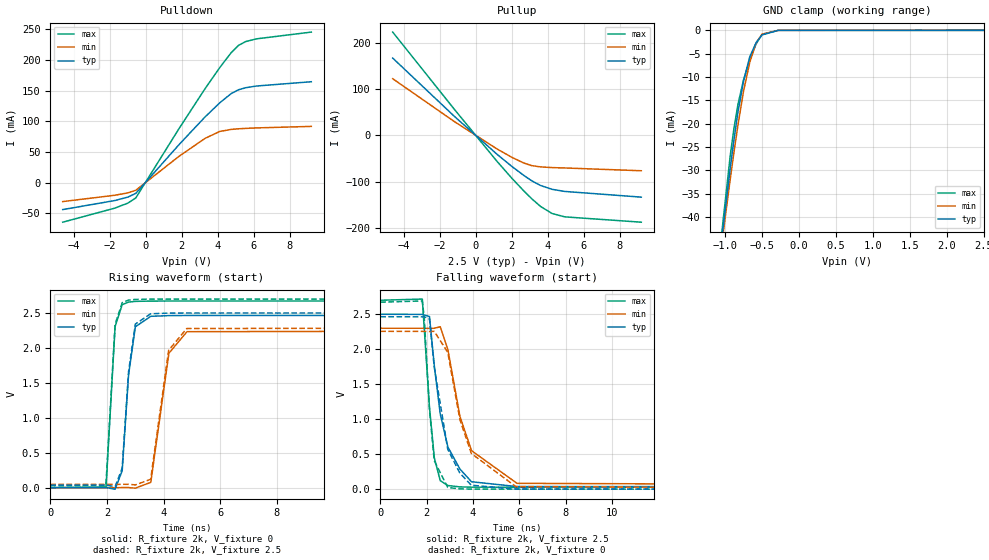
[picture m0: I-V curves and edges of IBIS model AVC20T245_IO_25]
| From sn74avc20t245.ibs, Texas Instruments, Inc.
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[Model]   AVC20T245_IO_25
Model_type  I/O
Vinl=0.7
Vinh=1.6
Enable   Active-Low
Vref =   0
Rref =   2000
Cref =   15p
Vmeas =   1.25
| variable   typ   min   max
C_comp   4.95pF   4.21pF   5.74pF
| C_pullup   4.12pF   3.17pF   5.55pF
| C_pulldown   4.24pF   3.76pF   4.72pF
| C_tri-state   4.95pF   4.21pF   5.74pF
[Temperature Range]   40   100   -40
| Ambient temperature   25   85   -40
[Voltage range]   2.5   2.3   2.7
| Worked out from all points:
|   slope of the pulldown table from 0 to 0.375 V, typ, clamps not added: 29.4 ohm
|   slope of the pullup table from 0 to 0.375 V, typ, clamps not added: 28.8 ohm
|   GND clamp passes 1 mA (typ) near -0.50 V on its own axis
|   rising waveform, R_fixture 2k, V_fixture 0: 20-80 % time 248ps typ, 381ps min, 173ps max; typ from 0 V to 2.46 V
|   falling waveform, R_fixture 2k, V_fixture 2.5: 20-80 % time 727ps typ, 1.03ns min, 342ps max; typ from 2.5 V to 0.036 V
|   rising waveform, R_fixture 2k, V_fixture 2.5: 20-80 % time 247ps typ, 377ps min, 173ps max; typ from 0.036 V to 2.5 V
|   falling waveform, R_fixture 2k, V_fixture 0: 20-80 % time 721ps typ, 1.03ns min, 334ps max; typ from 2.46 V to 0 V
[GND Clamp]
| AVC20T245_IO_25
|   Voltage   I(typ)   I(min)   I(max)
-4.6V     -597.8mA   -546.6mA   -662.5mA
-1.105V   -52.8mA    -53.15mA   -52.37mA
-1.08V    -49.35mA   -50.03mA   -48.48mA
-930mV    -29.5mA    -31.88mA   -26.82mA
-880mV    -23.45mA   -26.17mA   -21.02mA
-825mV    -17.44mA   -20.22mA   -15.81mA
-750mV    -10.86mA   -13.03mA   -10.61mA
-665mV    -5.629mA   -6.786mA   -6.326mA
-580mV    -2.642mA   -2.683mA   -2.914mA
-500mV    -988.4uA   -823.5uA   -890.7uA
-280mV    -5.263uA   -7.282uA   -1.131uA
2.5V      1.201nA    546.5nA    148.6pA
[Pulldown]
| AVC20T245_IO_25
|   Voltage   I(typ)   I(min)   I(max)
-4.6V     -43.76mA   -30.71mA   -64.27mA
-1.71V    -29.04mA   -20.44mA   -41.4mA
-985mV    -23.44mA   -16.53mA   -33.24mA
-545mV    -17.41mA   -12.35mA   -24.86mA
1.85V     61.76mA    42.85mA    87.78mA
3.295V    106.9mA    72.08mA    152.8mA
4.12V     130.1mA    83.49mA    187.5mA
4.755V    145.2mA    86.77mA    211.8mA
5.15V     151.2mA    87.75mA    223.4mA
5.55V     154.6mA    88.43mA    229.7mA
6.155V    157.4mA    89.2mA     234.2mA
9.2V      164.4mA    91.67mA    245.2mA
[Pullup]
| AVC20T245_IO_25
|   Voltage   I(typ)   I(min)   I(max)
-4.6V     167.2mA    122.6mA    223.3mA
-1.155V   40.55mA    29.45mA    55.44mA
1.195V    -40.71mA   -29.18mA   -56.05mA
2.025V    -67.14mA   -47.36mA   -92.77mA
2.69V     -86.59mA   -59.63mA   -120.2mA
3.115V    -97.78mA   -65.03mA   -136.5mA
3.61V     -108mA     -67.79mA   -153.3mA
4.245V    -116.2mA   -69.29mA   -168.4mA
4.95V     -120.8mA   -70.1mA    -175.7mA
9.2V      -133.1mA   -76.13mA   -187.2mA
[Ramp]
| AVC20T245_IO_25
| variable   typ   min   max
dV/dt_r   1.50/2.55E-10   1.37/3.90E-10   1.62/1.82E-10
dV/dt_f   1.49/7.30E-10   1.37/1.04E-09   1.61/3.44E-10
R_load = 2k
[Rising Waveform]
| AVC20T245_IO_25
R_fixture =   2k
C_fixture =   0
L_fixture =   0
V_fixture =   0
V_fixture_min = 0
V_fixture_max = 0
|   Time   V(typ)   V(min)   V(max)
0s        27.72nV    106.5nV    1.06nV
1.97ns    1.566mV    -36.35uV   11.32mV
2.29ns    -21.4mV    -1.633uV   2.307V
2.54ns    241.6mV    1.691mV    2.619V
2.765ns   1.614V     1.522mV    2.657V
3.005ns   2.303V     -6.857mV   2.667V
3.55ns    2.453V     75.79mV    2.671V
4.19ns    2.463V     1.925V     2.672V
4.83ns    2.465V     2.233V     2.672V
34.99ns   2.465V     2.256V     2.672V
[Falling Waveform]
| AVC20T245_IO_25
R_fixture =   2k
C_fixture =   0
L_fixture =   0
V_fixture =   2.5
V_fixture_min = 2.3
V_fixture_max = 2.7
|   Time   V(typ)   V(min)   V(max)
0s        2.5V       2.3V       2.7V
1.815ns   2.498V     2.3V       2.717V
2.125ns   2.467V     2.298V     1.169V
2.335ns   1.759V     2.3V       446.5mV
2.59ns    1.073V     2.321V     121.6mV
2.92ns    601.7mV    1.994V     52.07mV
3.44ns    287.2mV    1.04V      32.41mV
3.94ns    106.1mV    550.4mV    28.64mV
5.905ns   36.97mV    83.43mV    27.64mV
34.99ns   36.05mV    46.86mV    27.62mV
[Rising Waveform]
| AVC20T245_IO_25
R_fixture =   2k
C_fixture =   0
L_fixture =   0
V_fixture =   2.5
V_fixture_min = 2.3
V_fixture_max = 2.7
|   Time   V(typ)   V(min)   V(max)
0s        36.05mV    46.86mV    27.62mV
1.965ns   37.54mV    46.82mV    34.22mV
2.29ns    14.64mV    46.86mV    2.339V
2.54ns    279.7mV    48.55mV    2.648V
2.765ns   1.66V      48.31mV    2.685V
3.005ns   2.342V     39.88mV    2.695V
3.545ns   2.489V     119.7mV    2.699V
4.18ns    2.499V     1.966V     2.7V
4.82ns    2.5V       2.278V     2.7V
34.99ns   2.5V       2.3V       2.7V
[Falling Waveform]
| AVC20T245_IO_25
R_fixture =   2k
C_fixture =   0
L_fixture =   0
V_fixture =   0
V_fixture_min = 0
V_fixture_max = 0
|   Time   V(typ)   V(min)   V(max)
0s        2.465V     2.256V     2.672V
1.815ns   2.463V     2.255V     2.69V
1.9ns     2.464V     2.255V     2.445V
2.125ns   2.432V     2.253V     1.131V
2.33ns    1.746V     2.256V     407.7mV
2.915ns   568.4mV    1.955V     23.46mV
3.435ns   230.5mV    1V         4.487mV
3.93ns    56.57mV    510.4mV    968uV
5.855ns   812.7uV    36.59mV    20.96uV
34.99ns   315.6nV    270.4nV    142.7nV
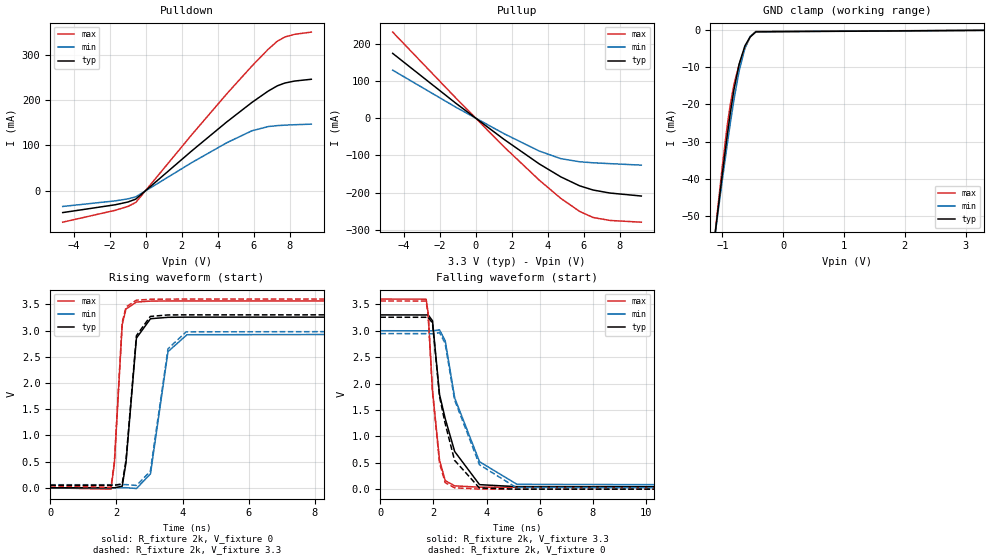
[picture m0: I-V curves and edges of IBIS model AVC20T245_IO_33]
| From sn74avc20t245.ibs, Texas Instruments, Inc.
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[Model]   AVC20T245_IO_33
Model_type  I/O
Vinl=0.8
Vinh=2.0
Enable   Active-Low
Vref =   0
Rref =   2000
Cref =   15p
Vmeas =   1.65
| variable   typ   min   max
C_comp   4.80pF   4.02pF   5.70pF
| C_pullup   3.86pF   2.95pF   5.16pF
| C_pulldown   4.06pF   3.58pF   4.65pF
| C_tri-state   4.80pF   4.02pF   5.70pF
[Temperature Range]   40   100   -40
| Ambient temperature   25   85   -40
[Voltage range]   3.3   3   3.6
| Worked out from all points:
|   slope of the pulldown table from 0 to 0.495 V, typ, clamps not added: 28.7 ohm
|   slope of the pullup table from 0 to 0.495 V, typ, clamps not added: 27.4 ohm
|   GND clamp passes 1 mA (typ) near -0.50 V on its own axis
|   rising waveform, R_fixture 2k, V_fixture 0: 20-80 % time 230ps typ, 350ps min, 168ps max; typ from 0 V to 3.26 V
|   falling waveform, R_fixture 2k, V_fixture 3.3: 20-80 % time 746ps typ, 999ps min, 329ps max; typ from 3.3 V to 0.046 V
|   rising waveform, R_fixture 2k, V_fixture 3.3: 20-80 % time 229ps typ, 351ps min, 168ps max; typ from 0.046 V to 3.3 V
|   falling waveform, R_fixture 2k, V_fixture 0: 20-80 % time 661ps typ, 999ps min, 325ps max; typ from 3.26 V to 0 V
[GND Clamp]
| AVC20T245_IO_33
|   Voltage   I(typ)   I(min)   I(max)
-4.6V     -597.8mA   -546.6mA   -662.5mA
-1.12V    -54.88mA   -55.04mA   -54.73mA
-1.09V    -50.72mA   -51.27mA   -50.03mA
-1V       -38.53mA   -40.19mA   -36.43mA
-920mV    -28.25mA   -30.71mA   -25.57mA
-870mV    -22.29mA   -25.06mA   -19.99mA
-810mV    -15.96mA   -18.69mA   -14.59mA
-725mV    -9.083mA   -10.96mA   -9.257mA
-630mV    -4.179mA   -4.838mA   -4.797mA
-545mV    -1.809mA   -1.649mA   -1.862mA
-450mV    -412.7uA   -343uA     -301.7uA
3.3V      1.631nA    2.398uA    228.2pA
[Pulldown]
| AVC20T245_IO_33
|   Voltage   I(typ)   I(min)   I(max)
-4.6V     -47.48mA   -33.99mA   -68.59mA
-1.68V    -30.25mA   -21.7mA    -42.42mA
-975mV    -24.15mA   -17.32mA   -33.81mA
-545mV    -17.86mA   -12.84mA   -25.24mA
2.54V     87.35mA    61.85mA    122.6mA
4.5V      151.6mA    105.9mA    213.3mA
5.905V    194.7mA    132.4mA    274.8mA
6.805V    219.6mA    141.6mA    311.5mA
7.315V    231.2mA    143.7mA    329.3mA
7.73V     237.3mA    144.7mA    338.5mA
8.275V    241.7mA    145.7mA    344.4mA
9.2V      245.6mA    146.9mA    349.3mA
[Pullup]
| AVC20T245_IO_33
|   Voltage   I(typ)   I(min)   I(max)
-4.6V     174.2mA    129.1mA    231.4mA
-1.105V   40.58mA    29.86mA    54.82mA
1.58V     -56.83mA   -41.58mA   -76.89mA
3.53V     -122.6mA   -88.07mA   -166.1mA
4.725V    -157.4mA   -108.5mA   -215.1mA
5.775V    -181.6mA   -117mA     -250.3mA
6.525V    -192.9mA   -119.7mA   -266.7mA
7.46V     -201mA     -122mA     -274.6mA
9.2V      -209mA     -126mA     -279.3mA
[Ramp]
| AVC20T245_IO_33
| variable   typ   min   max
dV/dt_r   1.97/2.35E-10   1.79/3.59E-10   2.16/1.73E-10
dV/dt_f   1.95/7.46E-10   1.78/1.00E-09   2.14/3.31E-10
R_load = 2k
[Rising Waveform]
| AVC20T245_IO_33
R_fixture =   2k
C_fixture =   0
L_fixture =   0
V_fixture =   0
V_fixture_min = 0
V_fixture_max = 0
|   Time   V(typ)   V(min)   V(max)
0s        38nV       120.5nV    1.922nV
1.835ns   1.604mV    -34.16uV   -26.16mV
1.94ns    172.5uV    6.665uV    471mV
2.175ns   29.48mV    952.4uV    3.116V
2.29ns    481mV      2.457mV    3.411V
2.605ns   2.855V     -13.98mV   3.543V
3.03ns    3.225V     265.1mV    3.561V
3.56ns    3.252V     2.598V     3.564V
4.135ns   3.255V     2.92V      3.564V
34.99ns   3.256V     2.946V     3.564V
[Falling Waveform]
| AVC20T245_IO_33
R_fixture =   2k
C_fixture =   0
L_fixture =   0
V_fixture =   3.3
V_fixture_min = 3
V_fixture_max = 3.6
|   Time   V(typ)   V(min)   V(max)
0s        3.3V       3V         3.6V
1.725ns   3.299V     2.999V     3.598V
1.8ns     3.302V     2.999V     3.34V
1.965ns   3.188V     2.998V     1.867V
2.23ns    1.791V     3.017V     546.7mV
2.445ns   1.333V     2.806V     161.9mV
2.8ns     712.8mV    1.728V     62.43mV
3.735ns   85.37mV    519.5mV    37.4mV
5.145ns   47.46mV    91.28mV    36.37mV
34.99ns   46.48mV    58.85mV    36.33mV
[Rising Waveform]
| AVC20T245_IO_33
R_fixture =   2k
C_fixture =   0
L_fixture =   0
V_fixture =   3.3
V_fixture_min = 3
V_fixture_max = 3.6
|   Time   V(typ)   V(min)   V(max)
0s        46.48mV    58.85mV    36.33mV
1.835ns   48.09mV    58.82mV    10.09mV
1.94ns    46.63mV    58.86mV    508.1mV
2.175ns   76.22mV    59.81mV    3.155V
2.29ns    529.5mV    61.31mV    3.449V
2.605ns   2.902V     44.69mV    3.579V
3.025ns   3.269V     313.7mV    3.596V
3.56ns    3.297V     2.652V     3.599V
4.11ns    3.299V     2.975V     3.6V
34.99ns   3.3V       3V         3.6V
[Falling Waveform]
| AVC20T245_IO_33
R_fixture =   2k
C_fixture =   0
L_fixture =   0
V_fixture =   0
V_fixture_min = 0
V_fixture_max = 0
|   Time   V(typ)   V(min)   V(max)
0s        3.256V     2.946V     3.564V
1.725ns   3.255V     2.945V     3.562V
1.8ns     3.258V     2.944V     3.305V
1.965ns   3.144V     2.943V     1.838V
2.23ns    1.754V     2.963V     492.9mV
2.44ns    1.246V     2.762V     124.7mV
2.795ns   546.8mV    1.692V     25.87mV
3.73ns    23.4mV     463.5mV    1.052mV
5.11ns    614.6uV    32.54mV    39.85uV
34.99ns   380.3nV    619.9nV    141.9nV
